###############################################################
#  Generated by:      Cadence Innovus 22.35-s091_1
#  OS:                Linux x86_64(Host ID EDA01.R760)
#  Generated on:      Tue Jul  7 21:02:47 2026
#  Design:            DCO
#  Command:           write_lef_abstract -5.8 -cutObsMinSpacing -PGpinLayers {M4 M5} -specifyTopLayer M5 -stripePin ../backup/signoff/DCO_postSignoff.lef
###############################################################

VERSION 5.8 ;

BUSBITCHARS "[]" ;
DIVIDERCHAR "/" ;

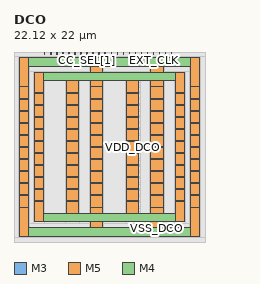
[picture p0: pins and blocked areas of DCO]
MACRO DCO
  CLASS BLOCK ;
  SIZE 22.120000 BY 22.000000 ;
  FOREIGN DCO 0.000000 0.000000 ;
  ORIGIN 0 0 ;
  SYMMETRY X Y R90 ;
  PIN EN
    DIRECTION INPUT ;
    USE SIGNAL ;
    PORT
      LAYER M3 ;
        RECT 15.435000 21.660000 15.485000 22.000000 ;
    END
  END EN
  PIN CC_SEL[5]
    DIRECTION INPUT ;
    USE SIGNAL ;
    PORT
      LAYER M3 ;
        RECT 11.235000 21.660000 11.285000 22.000000 ;
    END
  END CC_SEL[5]
  PIN CC_SEL[4]
    DIRECTION INPUT ;
    USE SIGNAL ;
    PORT
      LAYER M3 ;
        RECT 10.535000 21.660000 10.585000 22.000000 ;
    END
  END CC_SEL[4]
  PIN CC_SEL[3]
    DIRECTION INPUT ;
    USE SIGNAL ;
    PORT
      LAYER M3 ;
        RECT 9.835000 21.660000 9.885000 22.000000 ;
    END
  END CC_SEL[3]
  PIN CC_SEL[2]
    DIRECTION INPUT ;
    USE SIGNAL ;
    PORT
      LAYER M3 ;
        RECT 9.135000 21.660000 9.185000 22.000000 ;
    END
  END CC_SEL[2]
  PIN CC_SEL[1]
    DIRECTION INPUT ;
    USE SIGNAL ;
    PORT
      LAYER M3 ;
        RECT 8.435000 21.660000 8.485000 22.000000 ;
    END
  END CC_SEL[1]
  PIN CC_SEL[0]
    DIRECTION INPUT ;
    USE SIGNAL ;
    PORT
      LAYER M3 ;
        RECT 7.735000 21.660000 7.785000 22.000000 ;
    END
  END CC_SEL[0]
  PIN FC_SEL[5]
    DIRECTION INPUT ;
    USE SIGNAL ;
    PORT
      LAYER M3 ;
        RECT 7.035000 21.660000 7.085000 22.000000 ;
    END
  END FC_SEL[5]
  PIN FC_SEL[4]
    DIRECTION INPUT ;
    USE SIGNAL ;
    PORT
      LAYER M3 ;
        RECT 6.335000 21.660000 6.385000 22.000000 ;
    END
  END FC_SEL[4]
  PIN FC_SEL[3]
    DIRECTION INPUT ;
    USE SIGNAL ;
    PORT
      LAYER M3 ;
        RECT 5.635000 21.660000 5.685000 22.000000 ;
    END
  END FC_SEL[3]
  PIN FC_SEL[2]
    DIRECTION INPUT ;
    USE SIGNAL ;
    PORT
      LAYER M3 ;
        RECT 4.935000 21.660000 4.985000 22.000000 ;
    END
  END FC_SEL[2]
  PIN FC_SEL[1]
    DIRECTION INPUT ;
    USE SIGNAL ;
    PORT
      LAYER M3 ;
        RECT 4.235000 21.660000 4.285000 22.000000 ;
    END
  END FC_SEL[1]
  PIN FC_SEL[0]
    DIRECTION INPUT ;
    USE SIGNAL ;
    PORT
      LAYER M3 ;
        RECT 3.535000 21.660000 3.585000 22.000000 ;
    END
  END FC_SEL[0]
  PIN EXT_CLK
    DIRECTION INPUT ;
    USE SIGNAL ;
    PORT
      LAYER M3 ;
        RECT 16.135000 21.660000 16.185000 22.000000 ;
    END
  END EXT_CLK
  PIN CLK_SEL
    DIRECTION INPUT ;
    USE SIGNAL ;
    PORT
      LAYER M3 ;
        RECT 13.335000 21.660000 13.385000 22.000000 ;
    END
  END CLK_SEL
  PIN DIV_SEL[1]
    DIRECTION INPUT ;
    USE SIGNAL ;
    PORT
      LAYER M3 ;
        RECT 14.735000 21.660000 14.785000 22.000000 ;
    END
  END DIV_SEL[1]
  PIN DIV_SEL[0]
    DIRECTION INPUT ;
    USE SIGNAL ;
    PORT
      LAYER M3 ;
        RECT 14.035000 21.660000 14.085000 22.000000 ;
    END
  END DIV_SEL[0]
  PIN FREQ_SEL[1]
    DIRECTION INPUT ;
    USE SIGNAL ;
    PORT
      LAYER M3 ;
        RECT 17.535000 21.660000 17.585000 22.000000 ;
    END
  END FREQ_SEL[1]
  PIN FREQ_SEL[0]
    DIRECTION INPUT ;
    USE SIGNAL ;
    PORT
      LAYER M3 ;
        RECT 16.835000 21.660000 16.885000 22.000000 ;
    END
  END FREQ_SEL[0]
  PIN CLK
    DIRECTION OUTPUT ;
    USE SIGNAL ;
    PORT
      LAYER M3 ;
        RECT 11.935000 21.660000 11.985000 22.000000 ;
    END
  END CLK
  PIN CLK_DIV
    DIRECTION OUTPUT ;
    USE SIGNAL ;
    PORT
      LAYER M3 ;
        RECT 12.635000 21.660000 12.685000 22.000000 ;
    END
  END CLK_DIV
  PIN RSTN
    DIRECTION INPUT ;
    USE SIGNAL ;
    PORT
      LAYER M3 ;
        RECT 18.235000 21.660000 18.285000 22.000000 ;
    END
  END RSTN
  PIN VDD_DCO
    DIRECTION INOUT ;
    USE POWER ;
    PORT
      LAYER M5 ;
        RECT 13.060000 2.350000 14.460000 19.650000 ;
    END
    PORT
      LAYER M5 ;
        RECT 6.060000 2.350000 7.460000 19.650000 ;
    END

# P/G power stripe data as pin
    PORT
      LAYER M4 ;
        RECT 2.380000 2.350000 19.740000 3.350000 ;
        RECT 2.380000 18.650000 19.740000 19.650000 ;
        RECT 2.380000 4.650000 3.380000 4.750000 ;
        RECT 6.060000 4.650000 7.460000 4.750000 ;
        RECT 2.380000 7.450000 3.380000 7.550000 ;
        RECT 2.380000 6.050000 3.380000 6.150000 ;
        RECT 2.380000 10.250000 3.380000 10.350000 ;
        RECT 2.380000 8.850000 3.380000 8.950000 ;
        RECT 6.060000 6.050000 7.460000 6.150000 ;
        RECT 6.060000 7.450000 7.460000 7.550000 ;
        RECT 6.060000 10.250000 7.460000 10.350000 ;
        RECT 6.060000 8.850000 7.460000 8.950000 ;
        RECT 13.060000 4.650000 14.460000 4.750000 ;
        RECT 18.740000 4.650000 19.740000 4.750000 ;
        RECT 13.060000 6.050000 14.460000 6.150000 ;
        RECT 13.060000 10.250000 14.460000 10.350000 ;
        RECT 13.060000 8.850000 14.460000 8.950000 ;
        RECT 13.060000 7.450000 14.460000 7.550000 ;
        RECT 18.740000 7.450000 19.740000 7.550000 ;
        RECT 18.740000 6.050000 19.740000 6.150000 ;
        RECT 18.740000 10.250000 19.740000 10.350000 ;
        RECT 18.740000 8.850000 19.740000 8.950000 ;
        RECT 2.380000 13.050000 3.380000 13.150000 ;
        RECT 2.380000 11.650000 3.380000 11.750000 ;
        RECT 2.380000 15.850000 3.380000 15.950000 ;
        RECT 2.380000 14.450000 3.380000 14.550000 ;
        RECT 6.060000 11.650000 7.460000 11.750000 ;
        RECT 6.060000 13.050000 7.460000 13.150000 ;
        RECT 6.060000 14.450000 7.460000 14.550000 ;
        RECT 6.060000 15.850000 7.460000 15.950000 ;
        RECT 2.380000 17.250000 3.380000 17.350000 ;
        RECT 6.060000 17.250000 7.460000 17.350000 ;
        RECT 13.060000 11.650000 14.460000 11.750000 ;
        RECT 13.060000 13.050000 14.460000 13.150000 ;
        RECT 13.060000 15.850000 14.460000 15.950000 ;
        RECT 13.060000 14.450000 14.460000 14.550000 ;
        RECT 18.740000 13.050000 19.740000 13.150000 ;
        RECT 18.740000 11.650000 19.740000 11.750000 ;
        RECT 18.740000 15.850000 19.740000 15.950000 ;
        RECT 18.740000 14.450000 19.740000 14.550000 ;
        RECT 13.060000 17.250000 14.460000 17.350000 ;
        RECT 18.740000 17.250000 19.740000 17.350000 ;
      LAYER M5 ;
        RECT 13.060000 2.350000 14.460000 19.650000 ;
        RECT 6.060000 2.350000 7.460000 19.650000 ;
        RECT 18.740000 2.350000 19.740000 19.650000 ;
        RECT 2.380000 2.350000 3.380000 19.650000 ;
    END
# end of P/G power stripe data as pin

  END VDD_DCO
  PIN VSS_DCO
    DIRECTION INOUT ;
    USE GROUND ;
    PORT
      LAYER M5 ;
        RECT 15.860000 0.650000 17.260000 21.350000 ;
    END
    PORT
      LAYER M5 ;
        RECT 8.860000 0.650000 10.260000 21.350000 ;
    END

# P/G power stripe data as pin
    PORT
      LAYER M4 ;
        RECT 0.680000 0.650000 21.440000 1.650000 ;
        RECT 0.680000 20.350000 21.440000 21.350000 ;
        RECT 20.440000 10.950000 21.440000 11.050000 ;
        RECT 0.680000 10.950000 1.680000 11.050000 ;
        RECT 8.860000 10.950000 10.260000 11.050000 ;
        RECT 15.860000 10.950000 17.260000 11.050000 ;
        RECT 0.680000 3.950000 1.680000 4.050000 ;
        RECT 0.680000 5.350000 1.680000 5.450000 ;
        RECT 8.860000 5.350000 10.260000 5.450000 ;
        RECT 8.860000 3.950000 10.260000 4.050000 ;
        RECT 0.680000 8.150000 1.680000 8.250000 ;
        RECT 0.680000 6.750000 1.680000 6.850000 ;
        RECT 0.680000 9.550000 1.680000 9.650000 ;
        RECT 8.860000 8.150000 10.260000 8.250000 ;
        RECT 8.860000 9.550000 10.260000 9.650000 ;
        RECT 8.860000 6.750000 10.260000 6.850000 ;
        RECT 15.860000 3.950000 17.260000 4.050000 ;
        RECT 15.860000 5.350000 17.260000 5.450000 ;
        RECT 20.440000 3.950000 21.440000 4.050000 ;
        RECT 20.440000 5.350000 21.440000 5.450000 ;
        RECT 15.860000 6.750000 17.260000 6.850000 ;
        RECT 15.860000 9.550000 17.260000 9.650000 ;
        RECT 15.860000 8.150000 17.260000 8.250000 ;
        RECT 20.440000 8.150000 21.440000 8.250000 ;
        RECT 20.440000 6.750000 21.440000 6.850000 ;
        RECT 20.440000 9.550000 21.440000 9.650000 ;
        RECT 0.680000 13.750000 1.680000 13.850000 ;
        RECT 0.680000 12.350000 1.680000 12.450000 ;
        RECT 0.680000 15.150000 1.680000 15.250000 ;
        RECT 8.860000 15.150000 10.260000 15.250000 ;
        RECT 8.860000 13.750000 10.260000 13.850000 ;
        RECT 8.860000 12.350000 10.260000 12.450000 ;
        RECT 0.680000 16.550000 1.680000 16.650000 ;
        RECT 0.680000 17.950000 1.680000 18.050000 ;
        RECT 8.860000 16.550000 10.260000 16.650000 ;
        RECT 8.860000 17.950000 10.260000 18.050000 ;
        RECT 15.860000 12.350000 17.260000 12.450000 ;
        RECT 15.860000 13.750000 17.260000 13.850000 ;
        RECT 15.860000 15.150000 17.260000 15.250000 ;
        RECT 20.440000 13.750000 21.440000 13.850000 ;
        RECT 20.440000 12.350000 21.440000 12.450000 ;
        RECT 20.440000 15.150000 21.440000 15.250000 ;
        RECT 15.860000 17.950000 17.260000 18.050000 ;
        RECT 15.860000 16.550000 17.260000 16.650000 ;
        RECT 20.440000 16.550000 21.440000 16.650000 ;
        RECT 20.440000 17.950000 21.440000 18.050000 ;
      LAYER M5 ;
        RECT 15.860000 0.650000 17.260000 21.350000 ;
        RECT 8.860000 0.650000 10.260000 21.350000 ;
        RECT 20.440000 0.650000 21.440000 21.350000 ;
        RECT 0.680000 0.650000 1.680000 21.350000 ;
    END
# end of P/G power stripe data as pin

  END VSS_DCO
  OBS
    LAYER M1 ;
      RECT 0.000000 0.000000 22.120000 22.000000 ;
    LAYER M2 ;
      RECT 0.000000 0.000000 22.120000 22.000000 ;
    LAYER M3 ;
      RECT 18.335000 21.580000 22.120000 22.000000 ;
      RECT 17.635000 21.580000 18.185000 22.000000 ;
      RECT 16.935000 21.580000 17.485000 22.000000 ;
      RECT 16.235000 21.580000 16.785000 22.000000 ;
      RECT 15.535000 21.580000 16.085000 22.000000 ;
      RECT 14.835000 21.580000 15.385000 22.000000 ;
      RECT 14.135000 21.580000 14.685000 22.000000 ;
      RECT 13.435000 21.580000 13.985000 22.000000 ;
      RECT 12.735000 21.580000 13.285000 22.000000 ;
      RECT 12.035000 21.580000 12.585000 22.000000 ;
      RECT 11.335000 21.580000 11.885000 22.000000 ;
      RECT 10.635000 21.580000 11.185000 22.000000 ;
      RECT 9.935000 21.580000 10.485000 22.000000 ;
      RECT 9.235000 21.580000 9.785000 22.000000 ;
      RECT 8.535000 21.580000 9.085000 22.000000 ;
      RECT 7.835000 21.580000 8.385000 22.000000 ;
      RECT 7.135000 21.580000 7.685000 22.000000 ;
      RECT 6.435000 21.580000 6.985000 22.000000 ;
      RECT 5.735000 21.580000 6.285000 22.000000 ;
      RECT 5.035000 21.580000 5.585000 22.000000 ;
      RECT 4.335000 21.580000 4.885000 22.000000 ;
      RECT 3.635000 21.580000 4.185000 22.000000 ;
      RECT 0.000000 21.580000 3.485000 22.000000 ;
      RECT 0.000000 0.000000 22.120000 21.580000 ;
    LAYER M4 ;
      RECT 0.000000 21.500000 22.120000 22.000000 ;
      RECT 21.590000 20.200000 22.120000 21.500000 ;
      RECT 0.000000 20.200000 0.530000 21.500000 ;
      RECT 0.000000 19.800000 22.120000 20.200000 ;
      RECT 19.890000 18.500000 22.120000 19.800000 ;
      RECT 0.000000 18.500000 2.230000 19.800000 ;
      RECT 0.000000 18.110000 22.120000 18.500000 ;
      RECT 21.500000 17.890000 22.120000 18.110000 ;
      RECT 17.320000 17.890000 20.380000 18.110000 ;
      RECT 10.320000 17.890000 15.800000 18.110000 ;
      RECT 1.740000 17.890000 8.800000 18.110000 ;
      RECT 0.000000 17.890000 0.620000 18.110000 ;
      RECT 0.000000 17.410000 22.120000 17.890000 ;
      RECT 19.800000 17.190000 22.120000 17.410000 ;
      RECT 14.520000 17.190000 18.680000 17.410000 ;
      RECT 7.520000 17.190000 13.000000 17.410000 ;
      RECT 3.440000 17.190000 6.000000 17.410000 ;
      RECT 0.000000 17.190000 2.320000 17.410000 ;
      RECT 0.000000 16.710000 22.120000 17.190000 ;
      RECT 21.500000 16.490000 22.120000 16.710000 ;
      RECT 17.320000 16.490000 20.380000 16.710000 ;
      RECT 10.320000 16.490000 15.800000 16.710000 ;
      RECT 1.740000 16.490000 8.800000 16.710000 ;
      RECT 0.000000 16.490000 0.620000 16.710000 ;
      RECT 0.000000 16.010000 22.120000 16.490000 ;
      RECT 19.800000 15.790000 22.120000 16.010000 ;
      RECT 14.520000 15.790000 18.680000 16.010000 ;
      RECT 7.520000 15.790000 13.000000 16.010000 ;
      RECT 3.440000 15.790000 6.000000 16.010000 ;
      RECT 0.000000 15.790000 2.320000 16.010000 ;
      RECT 0.000000 15.310000 22.120000 15.790000 ;
      RECT 21.500000 15.090000 22.120000 15.310000 ;
      RECT 17.320000 15.090000 20.380000 15.310000 ;
      RECT 10.320000 15.090000 15.800000 15.310000 ;
      RECT 1.740000 15.090000 8.800000 15.310000 ;
      RECT 0.000000 15.090000 0.620000 15.310000 ;
      RECT 0.000000 14.610000 22.120000 15.090000 ;
      RECT 19.800000 14.390000 22.120000 14.610000 ;
      RECT 14.520000 14.390000 18.680000 14.610000 ;
      RECT 7.520000 14.390000 13.000000 14.610000 ;
      RECT 3.440000 14.390000 6.000000 14.610000 ;
      RECT 0.000000 14.390000 2.320000 14.610000 ;
      RECT 0.000000 13.910000 22.120000 14.390000 ;
      RECT 21.500000 13.690000 22.120000 13.910000 ;
      RECT 17.320000 13.690000 20.380000 13.910000 ;
      RECT 10.320000 13.690000 15.800000 13.910000 ;
      RECT 1.740000 13.690000 8.800000 13.910000 ;
      RECT 0.000000 13.690000 0.620000 13.910000 ;
      RECT 0.000000 13.210000 22.120000 13.690000 ;
      RECT 19.800000 12.990000 22.120000 13.210000 ;
      RECT 14.520000 12.990000 18.680000 13.210000 ;
      RECT 7.520000 12.990000 13.000000 13.210000 ;
      RECT 3.440000 12.990000 6.000000 13.210000 ;
      RECT 0.000000 12.990000 2.320000 13.210000 ;
      RECT 0.000000 12.510000 22.120000 12.990000 ;
      RECT 21.500000 12.290000 22.120000 12.510000 ;
      RECT 17.320000 12.290000 20.380000 12.510000 ;
      RECT 10.320000 12.290000 15.800000 12.510000 ;
      RECT 1.740000 12.290000 8.800000 12.510000 ;
      RECT 0.000000 12.290000 0.620000 12.510000 ;
      RECT 0.000000 11.810000 22.120000 12.290000 ;
      RECT 19.800000 11.590000 22.120000 11.810000 ;
      RECT 14.520000 11.590000 18.680000 11.810000 ;
      RECT 7.520000 11.590000 13.000000 11.810000 ;
      RECT 3.440000 11.590000 6.000000 11.810000 ;
      RECT 0.000000 11.590000 2.320000 11.810000 ;
      RECT 0.000000 11.110000 22.120000 11.590000 ;
      RECT 21.500000 10.890000 22.120000 11.110000 ;
      RECT 17.320000 10.890000 20.380000 11.110000 ;
      RECT 10.320000 10.890000 15.800000 11.110000 ;
      RECT 1.740000 10.890000 8.800000 11.110000 ;
      RECT 0.000000 10.890000 0.620000 11.110000 ;
      RECT 0.000000 10.410000 22.120000 10.890000 ;
      RECT 19.800000 10.190000 22.120000 10.410000 ;
      RECT 14.520000 10.190000 18.680000 10.410000 ;
      RECT 7.520000 10.190000 13.000000 10.410000 ;
      RECT 3.440000 10.190000 6.000000 10.410000 ;
      RECT 0.000000 10.190000 2.320000 10.410000 ;
      RECT 0.000000 9.710000 22.120000 10.190000 ;
      RECT 21.500000 9.490000 22.120000 9.710000 ;
      RECT 17.320000 9.490000 20.380000 9.710000 ;
      RECT 10.320000 9.490000 15.800000 9.710000 ;
      RECT 1.740000 9.490000 8.800000 9.710000 ;
      RECT 0.000000 9.490000 0.620000 9.710000 ;
      RECT 0.000000 9.010000 22.120000 9.490000 ;
      RECT 19.800000 8.790000 22.120000 9.010000 ;
      RECT 14.520000 8.790000 18.680000 9.010000 ;
      RECT 7.520000 8.790000 13.000000 9.010000 ;
      RECT 3.440000 8.790000 6.000000 9.010000 ;
      RECT 0.000000 8.790000 2.320000 9.010000 ;
      RECT 0.000000 8.310000 22.120000 8.790000 ;
      RECT 21.500000 8.090000 22.120000 8.310000 ;
      RECT 17.320000 8.090000 20.380000 8.310000 ;
      RECT 10.320000 8.090000 15.800000 8.310000 ;
      RECT 1.740000 8.090000 8.800000 8.310000 ;
      RECT 0.000000 8.090000 0.620000 8.310000 ;
      RECT 0.000000 7.610000 22.120000 8.090000 ;
      RECT 19.800000 7.390000 22.120000 7.610000 ;
      RECT 14.520000 7.390000 18.680000 7.610000 ;
      RECT 7.520000 7.390000 13.000000 7.610000 ;
      RECT 3.440000 7.390000 6.000000 7.610000 ;
      RECT 0.000000 7.390000 2.320000 7.610000 ;
      RECT 0.000000 6.910000 22.120000 7.390000 ;
      RECT 21.500000 6.690000 22.120000 6.910000 ;
      RECT 17.320000 6.690000 20.380000 6.910000 ;
      RECT 10.320000 6.690000 15.800000 6.910000 ;
      RECT 1.740000 6.690000 8.800000 6.910000 ;
      RECT 0.000000 6.690000 0.620000 6.910000 ;
      RECT 0.000000 6.210000 22.120000 6.690000 ;
      RECT 19.800000 5.990000 22.120000 6.210000 ;
      RECT 14.520000 5.990000 18.680000 6.210000 ;
      RECT 7.520000 5.990000 13.000000 6.210000 ;
      RECT 3.440000 5.990000 6.000000 6.210000 ;
      RECT 0.000000 5.990000 2.320000 6.210000 ;
      RECT 0.000000 5.510000 22.120000 5.990000 ;
      RECT 21.500000 5.290000 22.120000 5.510000 ;
      RECT 17.320000 5.290000 20.380000 5.510000 ;
      RECT 10.320000 5.290000 15.800000 5.510000 ;
      RECT 1.740000 5.290000 8.800000 5.510000 ;
      RECT 0.000000 5.290000 0.620000 5.510000 ;
      RECT 0.000000 4.810000 22.120000 5.290000 ;
      RECT 19.800000 4.590000 22.120000 4.810000 ;
      RECT 14.520000 4.590000 18.680000 4.810000 ;
      RECT 7.520000 4.590000 13.000000 4.810000 ;
      RECT 3.440000 4.590000 6.000000 4.810000 ;
      RECT 0.000000 4.590000 2.320000 4.810000 ;
      RECT 0.000000 4.110000 22.120000 4.590000 ;
      RECT 21.500000 3.890000 22.120000 4.110000 ;
      RECT 17.320000 3.890000 20.380000 4.110000 ;
      RECT 10.320000 3.890000 15.800000 4.110000 ;
      RECT 1.740000 3.890000 8.800000 4.110000 ;
      RECT 0.000000 3.890000 0.620000 4.110000 ;
      RECT 0.000000 3.500000 22.120000 3.890000 ;
      RECT 19.890000 2.200000 22.120000 3.500000 ;
      RECT 0.000000 2.200000 2.230000 3.500000 ;
      RECT 0.000000 1.800000 22.120000 2.200000 ;
      RECT 21.590000 0.500000 22.120000 1.800000 ;
      RECT 0.000000 0.500000 0.530000 1.800000 ;
      RECT 0.000000 0.000000 22.120000 0.500000 ;
    LAYER M5 ;
      RECT 0.000000 21.500000 22.120000 22.000000 ;
      RECT 17.410000 19.800000 20.290000 21.500000 ;
      RECT 10.410000 19.800000 15.710000 21.500000 ;
      RECT 1.830000 19.800000 8.710000 21.500000 ;
      RECT 19.890000 2.200000 20.290000 19.800000 ;
      RECT 17.410000 2.200000 18.590000 19.800000 ;
      RECT 14.610000 2.200000 15.710000 19.800000 ;
      RECT 10.410000 2.200000 12.910000 19.800000 ;
      RECT 7.610000 2.200000 8.710000 19.800000 ;
      RECT 3.530000 2.200000 5.910000 19.800000 ;
      RECT 1.830000 2.200000 2.230000 19.800000 ;
      RECT 21.590000 0.500000 22.120000 21.500000 ;
      RECT 17.410000 0.500000 20.290000 2.200000 ;
      RECT 10.410000 0.500000 15.710000 2.200000 ;
      RECT 1.830000 0.500000 8.710000 2.200000 ;
      RECT 0.000000 0.500000 0.530000 21.500000 ;
      RECT 0.000000 0.000000 22.120000 0.500000 ;
  END
END DCO

END LIBRARY
